VERSION 5.7 ;
BUSBITCHARS "[]" ;
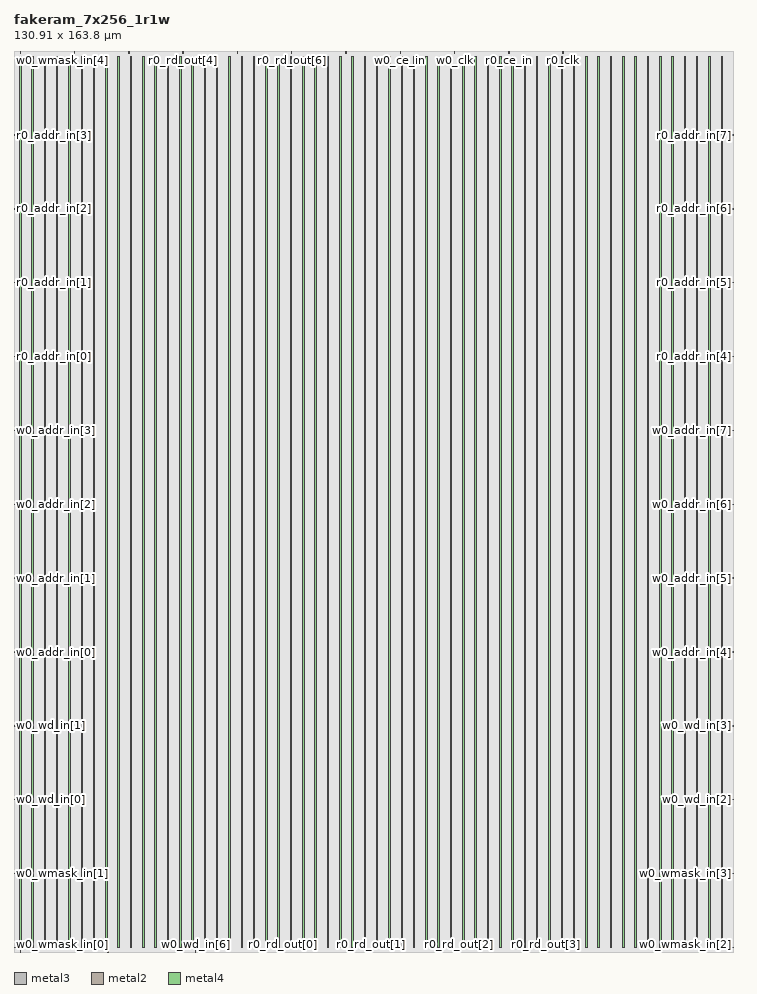
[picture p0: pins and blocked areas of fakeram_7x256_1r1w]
MACRO fakeram_7x256_1r1w
  FOREIGN fakeram_7x256_1r1w 0 0 ;
  SYMMETRY X Y R90 ;
  SIZE 130.910 BY 163.800 ;
  CLASS BLOCK ;
  PIN w0_wmask_in[0]
    DIRECTION INPUT ;
    USE SIGNAL ;
    SHAPE ABUTMENT ;
    PORT
      LAYER metal3 ;
      RECT 0.000 0.805 0.210 0.875 ;
    END
  END w0_wmask_in[0]
  PIN w0_wmask_in[1]
    DIRECTION INPUT ;
    USE SIGNAL ;
    SHAPE ABUTMENT ;
    PORT
      LAYER metal3 ;
      RECT 0.000 14.245 0.210 14.315 ;
    END
  END w0_wmask_in[1]
  PIN w0_wmask_in[2]
    DIRECTION INPUT ;
    USE SIGNAL ;
    SHAPE ABUTMENT ;
    PORT
      LAYER metal3 ;
      RECT 130.700 0.805 130.910 0.875 ;
    END
  END w0_wmask_in[2]
  PIN w0_wmask_in[3]
    DIRECTION INPUT ;
    USE SIGNAL ;
    SHAPE ABUTMENT ;
    PORT
      LAYER metal3 ;
      RECT 130.700 14.245 130.910 14.315 ;
    END
  END w0_wmask_in[3]
  PIN w0_wmask_in[4]
    DIRECTION INPUT ;
    USE SIGNAL ;
    SHAPE ABUTMENT ;
    PORT
      LAYER metal2 ;
      RECT 1.105 163.590 1.175 163.800 ;
    END
  END w0_wmask_in[4]
  PIN w0_wmask_in[5]
    DIRECTION INPUT ;
    USE SIGNAL ;
    SHAPE ABUTMENT ;
    PORT
      LAYER metal2 ;
      RECT 10.985 163.590 11.055 163.800 ;
    END
  END w0_wmask_in[5]
  PIN w0_wmask_in[6]
    DIRECTION INPUT ;
    USE SIGNAL ;
    SHAPE ABUTMENT ;
    PORT
      LAYER metal2 ;
      RECT 20.865 163.590 20.935 163.800 ;
    END
  END w0_wmask_in[6]
  PIN w0_wd_in[0]
    DIRECTION INPUT ;
    USE SIGNAL ;
    SHAPE ABUTMENT ;
    PORT
      LAYER metal3 ;
      RECT 0.000 27.685 0.210 27.755 ;
    END
  END w0_wd_in[0]
  PIN w0_wd_in[1]
    DIRECTION INPUT ;
    USE SIGNAL ;
    SHAPE ABUTMENT ;
    PORT
      LAYER metal3 ;
      RECT 0.000 41.125 0.210 41.195 ;
    END
  END w0_wd_in[1]
  PIN w0_wd_in[2]
    DIRECTION INPUT ;
    USE SIGNAL ;
    SHAPE ABUTMENT ;
    PORT
      LAYER metal3 ;
      RECT 130.700 27.685 130.910 27.755 ;
    END
  END w0_wd_in[2]
  PIN w0_wd_in[3]
    DIRECTION INPUT ;
    USE SIGNAL ;
    SHAPE ABUTMENT ;
    PORT
      LAYER metal3 ;
      RECT 130.700 41.125 130.910 41.195 ;
    END
  END w0_wd_in[3]
  PIN w0_wd_in[4]
    DIRECTION OUTPUT ;
    USE SIGNAL ;
    SHAPE ABUTMENT ;
    PORT
      LAYER metal2 ;
      RECT 1.105 0.000 1.175 0.210 ;
    END
  END w0_wd_in[4]
  PIN w0_wd_in[5]
    DIRECTION OUTPUT ;
    USE SIGNAL ;
    SHAPE ABUTMENT ;
    PORT
      LAYER metal2 ;
      RECT 17.065 0.000 17.135 0.210 ;
    END
  END w0_wd_in[5]
  PIN w0_wd_in[6]
    DIRECTION OUTPUT ;
    USE SIGNAL ;
    SHAPE ABUTMENT ;
    PORT
      LAYER metal2 ;
      RECT 33.025 0.000 33.095 0.210 ;
    END
  END w0_wd_in[6]
  PIN r0_rd_out[0]
    DIRECTION OUTPUT ;
    USE SIGNAL ;
    SHAPE ABUTMENT ;
    PORT
      LAYER metal2 ;
      RECT 48.985 0.000 49.055 0.210 ;
    END
  END r0_rd_out[0]
  PIN r0_rd_out[1]
    DIRECTION OUTPUT ;
    USE SIGNAL ;
    SHAPE ABUTMENT ;
    PORT
      LAYER metal2 ;
      RECT 64.945 0.000 65.015 0.210 ;
    END
  END r0_rd_out[1]
  PIN r0_rd_out[2]
    DIRECTION OUTPUT ;
    USE SIGNAL ;
    SHAPE ABUTMENT ;
    PORT
      LAYER metal2 ;
      RECT 80.905 0.000 80.975 0.210 ;
    END
  END r0_rd_out[2]
  PIN r0_rd_out[3]
    DIRECTION OUTPUT ;
    USE SIGNAL ;
    SHAPE ABUTMENT ;
    PORT
      LAYER metal2 ;
      RECT 96.865 0.000 96.935 0.210 ;
    END
  END r0_rd_out[3]
  PIN r0_rd_out[4]
    DIRECTION OUTPUT ;
    USE SIGNAL ;
    SHAPE ABUTMENT ;
    PORT
      LAYER metal2 ;
      RECT 30.745 163.590 30.815 163.800 ;
    END
  END r0_rd_out[4]
  PIN r0_rd_out[5]
    DIRECTION OUTPUT ;
    USE SIGNAL ;
    SHAPE ABUTMENT ;
    PORT
      LAYER metal2 ;
      RECT 40.625 163.590 40.695 163.800 ;
    END
  END r0_rd_out[5]
  PIN r0_rd_out[6]
    DIRECTION OUTPUT ;
    USE SIGNAL ;
    SHAPE ABUTMENT ;
    PORT
      LAYER metal2 ;
      RECT 50.505 163.590 50.575 163.800 ;
    END
  END r0_rd_out[6]
  PIN w0_addr_in[0]
    DIRECTION INPUT ;
    USE SIGNAL ;
    SHAPE ABUTMENT ;
    PORT
      LAYER metal3 ;
      RECT 0.000 54.565 0.210 54.635 ;
    END
  END w0_addr_in[0]
  PIN w0_addr_in[1]
    DIRECTION INPUT ;
    USE SIGNAL ;
    SHAPE ABUTMENT ;
    PORT
      LAYER metal3 ;
      RECT 0.000 68.005 0.210 68.075 ;
    END
  END w0_addr_in[1]
  PIN w0_addr_in[2]
    DIRECTION INPUT ;
    USE SIGNAL ;
    SHAPE ABUTMENT ;
    PORT
      LAYER metal3 ;
      RECT 0.000 81.445 0.210 81.515 ;
    END
  END w0_addr_in[2]
  PIN w0_addr_in[3]
    DIRECTION INPUT ;
    USE SIGNAL ;
    SHAPE ABUTMENT ;
    PORT
      LAYER metal3 ;
      RECT 0.000 94.885 0.210 94.955 ;
    END
  END w0_addr_in[3]
  PIN w0_addr_in[4]
    DIRECTION INPUT ;
    USE SIGNAL ;
    SHAPE ABUTMENT ;
    PORT
      LAYER metal3 ;
      RECT 130.700 54.565 130.910 54.635 ;
    END
  END w0_addr_in[4]
  PIN w0_addr_in[5]
    DIRECTION INPUT ;
    USE SIGNAL ;
    SHAPE ABUTMENT ;
    PORT
      LAYER metal3 ;
      RECT 130.700 68.005 130.910 68.075 ;
    END
  END w0_addr_in[5]
  PIN w0_addr_in[6]
    DIRECTION INPUT ;
    USE SIGNAL ;
    SHAPE ABUTMENT ;
    PORT
      LAYER metal3 ;
      RECT 130.700 81.445 130.910 81.515 ;
    END
  END w0_addr_in[6]
  PIN w0_addr_in[7]
    DIRECTION INPUT ;
    USE SIGNAL ;
    SHAPE ABUTMENT ;
    PORT
      LAYER metal3 ;
      RECT 130.700 94.885 130.910 94.955 ;
    END
  END w0_addr_in[7]
  PIN r0_addr_in[0]
    DIRECTION INPUT ;
    USE SIGNAL ;
    SHAPE ABUTMENT ;
    PORT
      LAYER metal3 ;
      RECT 0.000 108.325 0.210 108.395 ;
    END
  END r0_addr_in[0]
  PIN r0_addr_in[1]
    DIRECTION INPUT ;
    USE SIGNAL ;
    SHAPE ABUTMENT ;
    PORT
      LAYER metal3 ;
      RECT 0.000 121.765 0.210 121.835 ;
    END
  END r0_addr_in[1]
  PIN r0_addr_in[2]
    DIRECTION INPUT ;
    USE SIGNAL ;
    SHAPE ABUTMENT ;
    PORT
      LAYER metal3 ;
      RECT 0.000 135.205 0.210 135.275 ;
    END
  END r0_addr_in[2]
  PIN r0_addr_in[3]
    DIRECTION INPUT ;
    USE SIGNAL ;
    SHAPE ABUTMENT ;
    PORT
      LAYER metal3 ;
      RECT 0.000 148.645 0.210 148.715 ;
    END
  END r0_addr_in[3]
  PIN r0_addr_in[4]
    DIRECTION INPUT ;
    USE SIGNAL ;
    SHAPE ABUTMENT ;
    PORT
      LAYER metal3 ;
      RECT 130.700 108.325 130.910 108.395 ;
    END
  END r0_addr_in[4]
  PIN r0_addr_in[5]
    DIRECTION INPUT ;
    USE SIGNAL ;
    SHAPE ABUTMENT ;
    PORT
      LAYER metal3 ;
      RECT 130.700 121.765 130.910 121.835 ;
    END
  END r0_addr_in[5]
  PIN r0_addr_in[6]
    DIRECTION INPUT ;
    USE SIGNAL ;
    SHAPE ABUTMENT ;
    PORT
      LAYER metal3 ;
      RECT 130.700 135.205 130.910 135.275 ;
    END
  END r0_addr_in[6]
  PIN r0_addr_in[7]
    DIRECTION INPUT ;
    USE SIGNAL ;
    SHAPE ABUTMENT ;
    PORT
      LAYER metal3 ;
      RECT 130.700 148.645 130.910 148.715 ;
    END
  END r0_addr_in[7]
  PIN w0_we_in
    DIRECTION INPUT ;
    USE SIGNAL ;
    SHAPE ABUTMENT ;
    PORT
      LAYER metal2 ;
      RECT 60.385 163.590 60.455 163.800 ;
    END
  END w0_we_in
  PIN w0_ce_in
    DIRECTION INPUT ;
    USE SIGNAL ;
    SHAPE ABUTMENT ;
    PORT
      LAYER metal2 ;
      RECT 70.265 163.590 70.335 163.800 ;
    END
  END w0_ce_in
  PIN w0_clk
    DIRECTION INPUT ;
    USE SIGNAL ;
    SHAPE ABUTMENT ;
    PORT
      LAYER metal2 ;
      RECT 80.145 163.590 80.215 163.800 ;
    END
  END w0_clk
  PIN r0_ce_in
    DIRECTION INPUT ;
    USE SIGNAL ;
    SHAPE ABUTMENT ;
    PORT
      LAYER metal2 ;
      RECT 90.025 163.590 90.095 163.800 ;
    END
  END r0_ce_in
  PIN r0_clk
    DIRECTION INPUT ;
    USE SIGNAL ;
    SHAPE ABUTMENT ;
    PORT
      LAYER metal2 ;
      RECT 99.905 163.590 99.975 163.800 ;
    END
  END r0_clk
  PIN VSS
    DIRECTION INOUT ;
    USE GROUND ;
    PORT
      LAYER metal4 ;
      RECT 1.000 0.840 1.280 162.960 ;
      RECT 3.240 0.840 3.520 162.960 ;
      RECT 5.480 0.840 5.760 162.960 ;
      RECT 7.720 0.840 8.000 162.960 ;
      RECT 9.960 0.840 10.240 162.960 ;
      RECT 12.200 0.840 12.480 162.960 ;
      RECT 14.440 0.840 14.720 162.960 ;
      RECT 16.680 0.840 16.960 162.960 ;
      RECT 18.920 0.840 19.200 162.960 ;
      RECT 21.160 0.840 21.440 162.960 ;
      RECT 23.400 0.840 23.680 162.960 ;
      RECT 25.640 0.840 25.920 162.960 ;
      RECT 27.880 0.840 28.160 162.960 ;
      RECT 30.120 0.840 30.400 162.960 ;
      RECT 32.360 0.840 32.640 162.960 ;
      RECT 34.600 0.840 34.880 162.960 ;
      RECT 36.840 0.840 37.120 162.960 ;
      RECT 39.080 0.840 39.360 162.960 ;
      RECT 41.320 0.840 41.600 162.960 ;
      RECT 43.560 0.840 43.840 162.960 ;
      RECT 45.800 0.840 46.080 162.960 ;
      RECT 48.040 0.840 48.320 162.960 ;
      RECT 50.280 0.840 50.560 162.960 ;
      RECT 52.520 0.840 52.800 162.960 ;
      RECT 54.760 0.840 55.040 162.960 ;
      RECT 57.000 0.840 57.280 162.960 ;
      RECT 59.240 0.840 59.520 162.960 ;
      RECT 61.480 0.840 61.760 162.960 ;
      RECT 63.720 0.840 64.000 162.960 ;
      RECT 65.960 0.840 66.240 162.960 ;
      RECT 68.200 0.840 68.480 162.960 ;
      RECT 70.440 0.840 70.720 162.960 ;
      RECT 72.680 0.840 72.960 162.960 ;
      RECT 74.920 0.840 75.200 162.960 ;
      RECT 77.160 0.840 77.440 162.960 ;
      RECT 79.400 0.840 79.680 162.960 ;
      RECT 81.640 0.840 81.920 162.960 ;
      RECT 83.880 0.840 84.160 162.960 ;
      RECT 86.120 0.840 86.400 162.960 ;
      RECT 88.360 0.840 88.640 162.960 ;
      RECT 90.600 0.840 90.880 162.960 ;
      RECT 92.840 0.840 93.120 162.960 ;
      RECT 95.080 0.840 95.360 162.960 ;
      RECT 97.320 0.840 97.600 162.960 ;
      RECT 99.560 0.840 99.840 162.960 ;
      RECT 101.800 0.840 102.080 162.960 ;
      RECT 104.040 0.840 104.320 162.960 ;
      RECT 106.280 0.840 106.560 162.960 ;
      RECT 108.520 0.840 108.800 162.960 ;
      RECT 110.760 0.840 111.040 162.960 ;
      RECT 113.000 0.840 113.280 162.960 ;
      RECT 115.240 0.840 115.520 162.960 ;
      RECT 117.480 0.840 117.760 162.960 ;
      RECT 119.720 0.840 120.000 162.960 ;
      RECT 121.960 0.840 122.240 162.960 ;
      RECT 124.200 0.840 124.480 162.960 ;
      RECT 126.440 0.840 126.720 162.960 ;
      RECT 128.680 0.840 128.960 162.960 ;
    END
  END VSS
  PIN VDD
    DIRECTION INOUT ;
    USE POWER ;
    PORT
      LAYER metal4 ;
      RECT 1.000 0.840 1.280 162.960 ;
      RECT 3.240 0.840 3.520 162.960 ;
      RECT 5.480 0.840 5.760 162.960 ;
      RECT 7.720 0.840 8.000 162.960 ;
      RECT 9.960 0.840 10.240 162.960 ;
      RECT 12.200 0.840 12.480 162.960 ;
      RECT 14.440 0.840 14.720 162.960 ;
      RECT 16.680 0.840 16.960 162.960 ;
      RECT 18.920 0.840 19.200 162.960 ;
      RECT 21.160 0.840 21.440 162.960 ;
      RECT 23.400 0.840 23.680 162.960 ;
      RECT 25.640 0.840 25.920 162.960 ;
      RECT 27.880 0.840 28.160 162.960 ;
      RECT 30.120 0.840 30.400 162.960 ;
      RECT 32.360 0.840 32.640 162.960 ;
      RECT 34.600 0.840 34.880 162.960 ;
      RECT 36.840 0.840 37.120 162.960 ;
      RECT 39.080 0.840 39.360 162.960 ;
      RECT 41.320 0.840 41.600 162.960 ;
      RECT 43.560 0.840 43.840 162.960 ;
      RECT 45.800 0.840 46.080 162.960 ;
      RECT 48.040 0.840 48.320 162.960 ;
      RECT 50.280 0.840 50.560 162.960 ;
      RECT 52.520 0.840 52.800 162.960 ;
      RECT 54.760 0.840 55.040 162.960 ;
      RECT 57.000 0.840 57.280 162.960 ;
      RECT 59.240 0.840 59.520 162.960 ;
      RECT 61.480 0.840 61.760 162.960 ;
      RECT 63.720 0.840 64.000 162.960 ;
      RECT 65.960 0.840 66.240 162.960 ;
      RECT 68.200 0.840 68.480 162.960 ;
      RECT 70.440 0.840 70.720 162.960 ;
      RECT 72.680 0.840 72.960 162.960 ;
      RECT 74.920 0.840 75.200 162.960 ;
      RECT 77.160 0.840 77.440 162.960 ;
      RECT 79.400 0.840 79.680 162.960 ;
      RECT 81.640 0.840 81.920 162.960 ;
      RECT 83.880 0.840 84.160 162.960 ;
      RECT 86.120 0.840 86.400 162.960 ;
      RECT 88.360 0.840 88.640 162.960 ;
      RECT 90.600 0.840 90.880 162.960 ;
      RECT 92.840 0.840 93.120 162.960 ;
      RECT 95.080 0.840 95.360 162.960 ;
      RECT 97.320 0.840 97.600 162.960 ;
      RECT 99.560 0.840 99.840 162.960 ;
      RECT 101.800 0.840 102.080 162.960 ;
      RECT 104.040 0.840 104.320 162.960 ;
      RECT 106.280 0.840 106.560 162.960 ;
      RECT 108.520 0.840 108.800 162.960 ;
      RECT 110.760 0.840 111.040 162.960 ;
      RECT 113.000 0.840 113.280 162.960 ;
      RECT 115.240 0.840 115.520 162.960 ;
      RECT 117.480 0.840 117.760 162.960 ;
      RECT 119.720 0.840 120.000 162.960 ;
      RECT 121.960 0.840 122.240 162.960 ;
      RECT 124.200 0.840 124.480 162.960 ;
      RECT 126.440 0.840 126.720 162.960 ;
      RECT 128.680 0.840 128.960 162.960 ;
    END
  END VDD
  OBS
    LAYER metal1 ;
    RECT 0 0 130.910 163.800 ;
    LAYER metal2 ;
    RECT 0 0 130.910 163.800 ;
    LAYER metal3 ;
    RECT 0 0 130.910 163.800 ;
    LAYER metal4 ;
    RECT 0 0 130.910 163.800 ;
    LAYER OVERLAP ;
    RECT 0 0 130.910 163.800 ;
  END
END fakeram_7x256_1r1w

END LIBRARY
